VERSION 5.8 ;
BUSBITCHARS "[]" ;
DIVIDERCHAR "/" ;

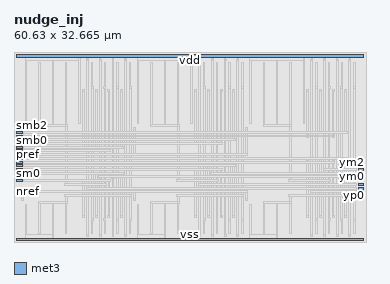
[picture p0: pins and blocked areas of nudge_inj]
MACRO nudge_inj
  CLASS BLOCK ;
  FOREIGN nudge_inj 0 0 ;
  ORIGIN 0 0 ;
  SIZE 60.630 BY 32.665 ;
  SYMMETRY X Y ;
  PIN nref
    DIRECTION INPUT ;
    USE SIGNAL ;
    PORT
      LAYER met3 ;
        RECT 0.460 8.455 1.400 8.795 ;
    END
  END nref
  PIN pref
    DIRECTION INPUT ;
    USE SIGNAL ;
    PORT
      LAYER met3 ;
        RECT 0.460 14.855 1.400 15.195 ;
    END
  END pref
  PIN sm0
    DIRECTION INPUT ;
    USE SIGNAL ;
    PORT
      LAYER met3 ;
        RECT 0.460 11.655 1.400 11.995 ;
    END
  END sm0
  PIN sm1
    DIRECTION INPUT ;
    USE SIGNAL ;
    PORT
      LAYER met3 ;
        RECT 0.460 12.935 1.400 13.275 ;
    END
  END sm1
  PIN sm2
    DIRECTION INPUT ;
    USE SIGNAL ;
    PORT
      LAYER met3 ;
        RECT 0.460 14.215 1.400 14.555 ;
    END
  END sm2
  PIN smb0
    DIRECTION INPUT ;
    USE SIGNAL ;
    PORT
      LAYER met3 ;
        RECT 0.460 16.135 1.400 16.475 ;
    END
  END smb0
  PIN smb1
    DIRECTION INPUT ;
    USE SIGNAL ;
    PORT
      LAYER met3 ;
        RECT 0.460 17.415 1.400 17.755 ;
    END
  END smb1
  PIN smb2
    DIRECTION INPUT ;
    USE SIGNAL ;
    PORT
      LAYER met3 ;
        RECT 0.460 18.695 1.400 19.035 ;
    END
  END smb2
  PIN sp0
    DIRECTION INPUT ;
    USE SIGNAL ;
    PORT
      LAYER met3 ;
        RECT 0.460 10.375 1.400 10.715 ;
    END
  END sp0
  PIN sp1
    DIRECTION INPUT ;
    USE SIGNAL ;
    PORT
      LAYER met3 ;
        RECT 0.460 12.295 1.400 12.635 ;
    END
  END sp1
  PIN sp2
    DIRECTION INPUT ;
    USE SIGNAL ;
    PORT
      LAYER met3 ;
        RECT 0.460 13.575 1.400 13.915 ;
    END
  END sp2
  PIN spb0
    DIRECTION INPUT ;
    USE SIGNAL ;
    PORT
      LAYER met3 ;
        RECT 0.460 15.495 1.400 15.835 ;
    END
  END spb0
  PIN spb1
    DIRECTION INPUT ;
    USE SIGNAL ;
    PORT
      LAYER met3 ;
        RECT 0.460 16.775 1.400 17.115 ;
    END
  END spb1
  PIN spb2
    DIRECTION INPUT ;
    USE SIGNAL ;
    PORT
      LAYER met3 ;
        RECT 0.460 18.055 1.400 18.395 ;
    END
  END spb2
  PIN vdd
    DIRECTION INOUT ;
    USE POWER ;
    PORT
      LAYER met3 ;
        RECT 0.460 31.705 60.170 32.205 ;
    END
  END vdd
  PIN vss
    DIRECTION INOUT ;
    USE GROUND ;
    PORT
      LAYER met3 ;
        RECT 0.460 0.185 60.170 0.685 ;
    END
  END vss
  PIN ym0
    DIRECTION OUTPUT ;
    USE SIGNAL ;
    PORT
      LAYER met3 ;
        RECT 59.230 11.015 60.170 11.355 ;
    END
  END ym0
  PIN ym1
    DIRECTION OUTPUT ;
    USE SIGNAL ;
    PORT
      LAYER met3 ;
        RECT 59.230 11.655 60.170 11.995 ;
    END
  END ym1
  PIN ym2
    DIRECTION OUTPUT ;
    USE SIGNAL ;
    PORT
      LAYER met3 ;
        RECT 59.230 12.295 60.170 12.635 ;
    END
  END ym2
  PIN yp0
    DIRECTION OUTPUT ;
    USE SIGNAL ;
    PORT
      LAYER met3 ;
        RECT 59.230 9.095 60.170 9.435 ;
    END
  END yp0
  PIN yp1
    DIRECTION OUTPUT ;
    USE SIGNAL ;
    PORT
      LAYER met3 ;
        RECT 59.230 9.735 60.170 10.075 ;
    END
  END yp1
  PIN yp2
    DIRECTION OUTPUT ;
    USE SIGNAL ;
    PORT
      LAYER met3 ;
        RECT 59.230 8.455 60.170 8.795 ;
    END
  END yp2
  OBS
    LAYER li1 ;
      RECT 0.000 0.000 60.630 32.665 ;
    LAYER met1 ;
      RECT 12.490 0.930 12.540 1.260 ;
      RECT 12.770 0.930 12.820 1.260 ;
      RECT 12.540 0.925 12.770 3.455 ;
      RECT 14.670 0.930 14.720 1.260 ;
      RECT 14.950 0.930 15.000 1.260 ;
      RECT 14.720 0.925 14.950 3.455 ;
      RECT 16.850 0.930 16.900 1.260 ;
      RECT 17.130 0.930 17.180 1.260 ;
      RECT 16.900 0.925 17.130 3.455 ;
      RECT 19.030 0.930 19.080 1.260 ;
      RECT 19.310 0.930 19.360 1.260 ;
      RECT 19.080 0.925 19.310 3.455 ;
      RECT 31.760 0.930 31.810 1.260 ;
      RECT 32.040 0.930 32.090 1.260 ;
      RECT 31.810 0.925 32.040 3.455 ;
      RECT 33.940 0.930 33.990 1.260 ;
      RECT 34.220 0.930 34.270 1.260 ;
      RECT 33.990 0.925 34.220 3.455 ;
      RECT 36.120 0.930 36.170 1.260 ;
      RECT 36.400 0.930 36.450 1.260 ;
      RECT 36.170 0.925 36.400 3.455 ;
      RECT 38.300 0.930 38.350 1.260 ;
      RECT 38.580 0.930 38.630 1.260 ;
      RECT 38.350 0.925 38.580 3.455 ;
      RECT 51.030 0.930 51.080 1.260 ;
      RECT 51.310 0.930 51.360 1.260 ;
      RECT 51.080 0.925 51.310 3.455 ;
      RECT 53.210 0.930 53.260 1.260 ;
      RECT 53.490 0.930 53.540 1.260 ;
      RECT 53.260 0.925 53.490 3.455 ;
      RECT 55.390 0.930 55.440 1.260 ;
      RECT 55.670 0.930 55.720 1.260 ;
      RECT 55.440 0.925 55.670 3.455 ;
      RECT 57.570 0.930 57.620 1.260 ;
      RECT 57.850 0.930 57.900 1.260 ;
      RECT 57.620 0.925 57.850 3.455 ;
      RECT 13.330 3.960 13.560 3.965 ;
      RECT 13.280 3.630 13.610 3.960 ;
      RECT 13.330 1.455 13.560 3.630 ;
      RECT 15.510 3.960 15.740 3.965 ;
      RECT 15.460 3.630 15.790 3.960 ;
      RECT 15.510 1.455 15.740 3.630 ;
      RECT 17.690 3.960 17.920 3.965 ;
      RECT 17.640 3.630 17.970 3.960 ;
      RECT 17.690 1.455 17.920 3.630 ;
      RECT 19.870 3.960 20.100 3.965 ;
      RECT 19.820 3.630 20.150 3.960 ;
      RECT 19.870 1.455 20.100 3.630 ;
      RECT 32.600 3.960 32.830 3.965 ;
      RECT 32.550 3.630 32.880 3.960 ;
      RECT 32.600 1.455 32.830 3.630 ;
      RECT 34.780 3.960 35.010 3.965 ;
      RECT 34.730 3.630 35.060 3.960 ;
      RECT 34.780 1.455 35.010 3.630 ;
      RECT 36.960 3.960 37.190 3.965 ;
      RECT 36.910 3.630 37.240 3.960 ;
      RECT 36.960 1.455 37.190 3.630 ;
      RECT 39.140 3.960 39.370 3.965 ;
      RECT 39.090 3.630 39.420 3.960 ;
      RECT 39.140 1.455 39.370 3.630 ;
      RECT 51.870 3.960 52.100 3.965 ;
      RECT 51.820 3.630 52.150 3.960 ;
      RECT 51.870 1.455 52.100 3.630 ;
      RECT 54.050 3.960 54.280 3.965 ;
      RECT 54.000 3.630 54.330 3.960 ;
      RECT 54.050 1.455 54.280 3.630 ;
      RECT 56.230 3.960 56.460 3.965 ;
      RECT 56.180 3.630 56.510 3.960 ;
      RECT 56.230 1.455 56.460 3.630 ;
      RECT 58.410 3.960 58.640 3.965 ;
      RECT 58.360 3.630 58.690 3.960 ;
      RECT 58.410 1.455 58.640 3.630 ;
      RECT 11.790 4.145 12.130 4.485 ;
      RECT 13.970 4.145 14.310 4.485 ;
      RECT 16.150 4.145 16.490 4.485 ;
      RECT 18.330 4.145 18.670 4.485 ;
      RECT 31.060 4.145 31.400 4.485 ;
      RECT 33.240 4.145 33.580 4.485 ;
      RECT 35.420 4.145 35.760 4.485 ;
      RECT 37.600 4.145 37.940 4.485 ;
      RECT 50.330 4.145 50.670 4.485 ;
      RECT 52.510 4.145 52.850 4.485 ;
      RECT 54.690 4.145 55.030 4.485 ;
      RECT 56.870 4.145 57.210 4.485 ;
      RECT 1.990 1.265 2.220 6.455 ;
      RECT 6.570 0.685 6.800 6.455 ;
      RECT 1.990 0.685 6.570 1.265 ;
      RECT 21.260 1.265 21.490 6.455 ;
      RECT 25.840 0.685 26.070 6.455 ;
      RECT 21.260 0.685 25.840 1.265 ;
      RECT 40.530 1.265 40.760 6.455 ;
      RECT 45.340 0.185 60.170 0.685 ;
      RECT 45.110 0.185 45.340 6.455 ;
      RECT 40.530 0.185 45.110 1.265 ;
      RECT 0.460 0.185 40.530 0.685 ;
      RECT 4.280 1.455 4.510 6.625 ;
      RECT 4.280 6.625 8.860 6.965 ;
      RECT 9.090 6.630 9.140 6.960 ;
      RECT 8.860 1.455 9.090 6.965 ;
      RECT 23.550 1.455 23.780 6.625 ;
      RECT 23.550 6.625 28.130 6.965 ;
      RECT 28.360 6.630 28.410 6.960 ;
      RECT 28.130 1.455 28.360 6.965 ;
      RECT 42.820 1.455 43.050 6.625 ;
      RECT 42.820 6.625 47.400 6.965 ;
      RECT 47.630 6.630 47.680 6.960 ;
      RECT 47.400 1.455 47.630 6.965 ;
      RECT 1.240 7.145 1.580 7.485 ;
      RECT 20.510 7.145 20.850 7.485 ;
      RECT 39.780 7.145 40.120 7.485 ;
      RECT 1.240 19.405 1.580 19.745 ;
      RECT 20.510 19.405 20.850 19.745 ;
      RECT 39.780 19.405 40.120 19.745 ;
      RECT 11.790 25.905 12.130 26.245 ;
      RECT 13.970 25.905 14.310 26.245 ;
      RECT 16.150 25.905 16.490 26.245 ;
      RECT 18.330 25.905 18.670 26.245 ;
      RECT 31.060 25.905 31.400 26.245 ;
      RECT 33.240 25.905 33.580 26.245 ;
      RECT 35.420 25.905 35.760 26.245 ;
      RECT 37.600 25.905 37.940 26.245 ;
      RECT 50.330 25.905 50.670 26.245 ;
      RECT 52.510 25.905 52.850 26.245 ;
      RECT 54.690 25.905 55.030 26.245 ;
      RECT 56.870 25.905 57.210 26.245 ;
      RECT 4.280 20.265 4.510 30.935 ;
      RECT 8.860 20.265 9.090 30.935 ;
      RECT 9.090 19.930 9.140 20.260 ;
      RECT 4.280 19.925 9.090 20.265 ;
      RECT 13.280 26.430 13.330 26.760 ;
      RECT 13.560 26.430 13.610 26.760 ;
      RECT 13.330 26.425 13.560 30.935 ;
      RECT 15.460 26.430 15.510 26.760 ;
      RECT 15.740 26.430 15.790 26.760 ;
      RECT 15.510 26.425 15.740 30.935 ;
      RECT 17.640 26.430 17.690 26.760 ;
      RECT 17.920 26.430 17.970 26.760 ;
      RECT 17.690 26.425 17.920 30.935 ;
      RECT 19.820 26.430 19.870 26.760 ;
      RECT 20.100 26.430 20.150 26.760 ;
      RECT 19.870 26.425 20.100 30.935 ;
      RECT 23.550 20.265 23.780 30.935 ;
      RECT 28.130 20.265 28.360 30.935 ;
      RECT 28.360 19.930 28.410 20.260 ;
      RECT 23.550 19.925 28.360 20.265 ;
      RECT 32.550 26.430 32.600 26.760 ;
      RECT 32.830 26.430 32.880 26.760 ;
      RECT 32.600 26.425 32.830 30.935 ;
      RECT 34.730 26.430 34.780 26.760 ;
      RECT 35.010 26.430 35.060 26.760 ;
      RECT 34.780 26.425 35.010 30.935 ;
      RECT 36.910 26.430 36.960 26.760 ;
      RECT 37.190 26.430 37.240 26.760 ;
      RECT 36.960 26.425 37.190 30.935 ;
      RECT 39.090 26.430 39.140 26.760 ;
      RECT 39.370 26.430 39.420 26.760 ;
      RECT 39.140 26.425 39.370 30.935 ;
      RECT 42.820 20.265 43.050 30.935 ;
      RECT 47.400 20.265 47.630 30.935 ;
      RECT 47.630 19.930 47.680 20.260 ;
      RECT 42.820 19.925 47.630 20.265 ;
      RECT 51.820 26.430 51.870 26.760 ;
      RECT 52.100 26.430 52.150 26.760 ;
      RECT 51.870 26.425 52.100 30.935 ;
      RECT 54.000 26.430 54.050 26.760 ;
      RECT 54.280 26.430 54.330 26.760 ;
      RECT 54.050 26.425 54.280 30.935 ;
      RECT 56.180 26.430 56.230 26.760 ;
      RECT 56.460 26.430 56.510 26.760 ;
      RECT 56.230 26.425 56.460 30.935 ;
      RECT 58.360 26.430 58.410 26.760 ;
      RECT 58.640 26.430 58.690 26.760 ;
      RECT 58.410 26.425 58.640 30.935 ;
      RECT 12.540 31.460 12.770 31.465 ;
      RECT 12.490 31.130 12.820 31.460 ;
      RECT 12.540 26.935 12.770 31.130 ;
      RECT 14.720 31.460 14.950 31.465 ;
      RECT 14.670 31.130 15.000 31.460 ;
      RECT 14.720 26.935 14.950 31.130 ;
      RECT 16.900 31.460 17.130 31.465 ;
      RECT 16.850 31.130 17.180 31.460 ;
      RECT 16.900 26.935 17.130 31.130 ;
      RECT 19.080 31.460 19.310 31.465 ;
      RECT 19.030 31.130 19.360 31.460 ;
      RECT 19.080 26.935 19.310 31.130 ;
      RECT 31.810 31.460 32.040 31.465 ;
      RECT 31.760 31.130 32.090 31.460 ;
      RECT 31.810 26.935 32.040 31.130 ;
      RECT 33.990 31.460 34.220 31.465 ;
      RECT 33.940 31.130 34.270 31.460 ;
      RECT 33.990 26.935 34.220 31.130 ;
      RECT 36.170 31.460 36.400 31.465 ;
      RECT 36.120 31.130 36.450 31.460 ;
      RECT 36.170 26.935 36.400 31.130 ;
      RECT 38.350 31.460 38.580 31.465 ;
      RECT 38.300 31.130 38.630 31.460 ;
      RECT 38.350 26.935 38.580 31.130 ;
      RECT 51.080 31.460 51.310 31.465 ;
      RECT 51.030 31.130 51.360 31.460 ;
      RECT 51.080 26.935 51.310 31.130 ;
      RECT 53.260 31.460 53.490 31.465 ;
      RECT 53.210 31.130 53.540 31.460 ;
      RECT 53.260 26.935 53.490 31.130 ;
      RECT 55.440 31.460 55.670 31.465 ;
      RECT 55.390 31.130 55.720 31.460 ;
      RECT 55.440 26.935 55.670 31.130 ;
      RECT 57.620 31.460 57.850 31.465 ;
      RECT 57.570 31.130 57.900 31.460 ;
      RECT 57.620 26.935 57.850 31.130 ;
      RECT 1.990 20.435 2.220 31.125 ;
      RECT 6.570 20.435 6.800 31.125 ;
      RECT 21.260 20.435 21.490 31.125 ;
      RECT 25.840 20.435 26.070 31.125 ;
      RECT 40.530 20.435 40.760 31.125 ;
      RECT 45.110 20.435 45.340 31.125 ;
      RECT 1.990 31.125 11.150 31.705 ;
      RECT 11.150 20.435 11.380 31.705 ;
      RECT 21.260 31.125 30.420 31.705 ;
      RECT 30.420 20.435 30.650 31.705 ;
      RECT 0.460 31.705 40.530 32.205 ;
      RECT 40.530 31.125 49.690 32.205 ;
      RECT 49.690 20.435 49.920 32.205 ;
      RECT 49.920 31.705 60.170 32.205 ;
    LAYER met2 ;
      RECT 0.460 0.185 60.170 0.685 ;
      RECT 8.790 7.800 9.160 8.170 ;
      RECT 8.825 6.960 9.125 7.800 ;
      RECT 8.810 6.630 9.140 6.960 ;
      RECT 28.060 7.800 28.430 8.170 ;
      RECT 28.095 6.960 28.395 7.800 ;
      RECT 28.080 6.630 28.410 6.960 ;
      RECT 47.330 7.800 47.700 8.170 ;
      RECT 47.365 6.960 47.665 7.800 ;
      RECT 47.350 6.630 47.680 6.960 ;
      RECT 1.225 8.440 1.595 8.810 ;
      RECT 1.260 7.480 1.560 8.440 ;
      RECT 1.245 7.150 1.575 7.480 ;
      RECT 20.495 8.440 20.865 8.810 ;
      RECT 20.530 7.480 20.830 8.440 ;
      RECT 20.515 7.150 20.845 7.480 ;
      RECT 39.765 8.440 40.135 8.810 ;
      RECT 39.800 7.480 40.100 8.440 ;
      RECT 39.785 7.150 40.115 7.480 ;
      RECT 11.775 10.360 12.145 10.730 ;
      RECT 11.810 4.480 12.110 10.360 ;
      RECT 11.795 4.150 12.125 4.480 ;
      RECT 16.135 10.360 16.505 10.730 ;
      RECT 16.170 4.480 16.470 10.360 ;
      RECT 16.155 4.150 16.485 4.480 ;
      RECT 13.955 11.640 14.325 12.010 ;
      RECT 13.990 4.480 14.290 11.640 ;
      RECT 13.975 4.150 14.305 4.480 ;
      RECT 18.315 11.640 18.685 12.010 ;
      RECT 18.350 4.480 18.650 11.640 ;
      RECT 18.335 4.150 18.665 4.480 ;
      RECT 31.045 12.280 31.415 12.650 ;
      RECT 31.080 4.480 31.380 12.280 ;
      RECT 31.065 4.150 31.395 4.480 ;
      RECT 35.405 12.280 35.775 12.650 ;
      RECT 35.440 4.480 35.740 12.280 ;
      RECT 35.425 4.150 35.755 4.480 ;
      RECT 33.225 12.920 33.595 13.290 ;
      RECT 33.260 4.480 33.560 12.920 ;
      RECT 33.245 4.150 33.575 4.480 ;
      RECT 37.585 12.920 37.955 13.290 ;
      RECT 37.620 4.480 37.920 12.920 ;
      RECT 37.605 4.150 37.935 4.480 ;
      RECT 50.315 13.560 50.685 13.930 ;
      RECT 50.350 4.480 50.650 13.560 ;
      RECT 50.335 4.150 50.665 4.480 ;
      RECT 54.675 13.560 55.045 13.930 ;
      RECT 54.710 4.480 55.010 13.560 ;
      RECT 54.695 4.150 55.025 4.480 ;
      RECT 52.495 14.200 52.865 14.570 ;
      RECT 52.530 4.480 52.830 14.200 ;
      RECT 52.515 4.150 52.845 4.480 ;
      RECT 56.855 14.200 57.225 14.570 ;
      RECT 56.890 4.480 57.190 14.200 ;
      RECT 56.875 4.150 57.205 4.480 ;
      RECT 1.245 19.410 1.575 19.740 ;
      RECT 1.260 15.210 1.560 19.410 ;
      RECT 1.225 14.840 1.595 15.210 ;
      RECT 20.515 19.410 20.845 19.740 ;
      RECT 20.530 15.210 20.830 19.410 ;
      RECT 20.495 14.840 20.865 15.210 ;
      RECT 39.785 19.410 40.115 19.740 ;
      RECT 39.800 15.210 40.100 19.410 ;
      RECT 39.765 14.840 40.135 15.210 ;
      RECT 8.810 19.930 9.140 20.260 ;
      RECT 8.825 10.090 9.125 19.930 ;
      RECT 8.790 9.720 9.160 10.090 ;
      RECT 28.080 19.930 28.410 20.260 ;
      RECT 28.095 10.730 28.395 19.930 ;
      RECT 28.060 10.360 28.430 10.730 ;
      RECT 47.350 19.930 47.680 20.260 ;
      RECT 47.365 10.730 47.665 19.930 ;
      RECT 47.330 10.360 47.700 10.730 ;
      RECT 11.795 25.910 12.125 26.240 ;
      RECT 11.810 15.850 12.110 25.910 ;
      RECT 11.775 15.480 12.145 15.850 ;
      RECT 13.975 25.910 14.305 26.240 ;
      RECT 13.990 16.490 14.290 25.910 ;
      RECT 13.955 16.120 14.325 16.490 ;
      RECT 16.155 25.910 16.485 26.240 ;
      RECT 16.170 15.850 16.470 25.910 ;
      RECT 16.135 15.480 16.505 15.850 ;
      RECT 18.335 25.910 18.665 26.240 ;
      RECT 18.350 16.490 18.650 25.910 ;
      RECT 18.315 16.120 18.685 16.490 ;
      RECT 31.065 25.910 31.395 26.240 ;
      RECT 31.080 17.130 31.380 25.910 ;
      RECT 31.045 16.760 31.415 17.130 ;
      RECT 33.245 25.910 33.575 26.240 ;
      RECT 33.260 17.770 33.560 25.910 ;
      RECT 33.225 17.400 33.595 17.770 ;
      RECT 35.425 25.910 35.755 26.240 ;
      RECT 35.440 17.130 35.740 25.910 ;
      RECT 35.405 16.760 35.775 17.130 ;
      RECT 37.605 25.910 37.935 26.240 ;
      RECT 37.620 17.770 37.920 25.910 ;
      RECT 37.585 17.400 37.955 17.770 ;
      RECT 50.335 25.910 50.665 26.240 ;
      RECT 50.350 18.410 50.650 25.910 ;
      RECT 50.315 18.040 50.685 18.410 ;
      RECT 52.515 25.910 52.845 26.240 ;
      RECT 52.530 19.050 52.830 25.910 ;
      RECT 52.495 18.680 52.865 19.050 ;
      RECT 54.695 25.910 55.025 26.240 ;
      RECT 54.710 18.410 55.010 25.910 ;
      RECT 54.675 18.040 55.045 18.410 ;
      RECT 56.875 25.910 57.205 26.240 ;
      RECT 56.890 19.050 57.190 25.910 ;
      RECT 56.855 18.680 57.225 19.050 ;
      RECT 13.280 26.430 13.610 26.760 ;
      RECT 13.295 10.090 13.595 26.430 ;
      RECT 13.260 9.720 13.630 10.090 ;
      RECT 13.295 3.960 13.595 9.720 ;
      RECT 13.280 3.630 13.610 3.960 ;
      RECT 15.460 26.430 15.790 26.760 ;
      RECT 15.475 10.090 15.775 26.430 ;
      RECT 15.440 9.720 15.810 10.090 ;
      RECT 15.475 3.960 15.775 9.720 ;
      RECT 15.460 3.630 15.790 3.960 ;
      RECT 17.640 26.430 17.970 26.760 ;
      RECT 17.655 8.170 17.955 26.430 ;
      RECT 17.620 7.800 17.990 8.170 ;
      RECT 17.655 3.960 17.955 7.800 ;
      RECT 17.640 3.630 17.970 3.960 ;
      RECT 19.820 26.430 20.150 26.760 ;
      RECT 19.835 8.170 20.135 26.430 ;
      RECT 19.800 7.800 20.170 8.170 ;
      RECT 19.835 3.960 20.135 7.800 ;
      RECT 19.820 3.630 20.150 3.960 ;
      RECT 32.550 26.430 32.880 26.760 ;
      RECT 32.565 10.730 32.865 26.430 ;
      RECT 32.530 10.360 32.900 10.730 ;
      RECT 32.565 3.960 32.865 10.360 ;
      RECT 32.550 3.630 32.880 3.960 ;
      RECT 34.730 26.430 35.060 26.760 ;
      RECT 34.745 10.730 35.045 26.430 ;
      RECT 34.710 10.360 35.080 10.730 ;
      RECT 34.745 3.960 35.045 10.360 ;
      RECT 34.730 3.630 35.060 3.960 ;
      RECT 36.910 26.430 37.240 26.760 ;
      RECT 36.925 8.170 37.225 26.430 ;
      RECT 36.890 7.800 37.260 8.170 ;
      RECT 36.925 3.960 37.225 7.800 ;
      RECT 36.910 3.630 37.240 3.960 ;
      RECT 39.090 26.430 39.420 26.760 ;
      RECT 39.105 8.170 39.405 26.430 ;
      RECT 39.070 7.800 39.440 8.170 ;
      RECT 39.105 3.960 39.405 7.800 ;
      RECT 39.090 3.630 39.420 3.960 ;
      RECT 51.820 26.430 52.150 26.760 ;
      RECT 51.835 10.730 52.135 26.430 ;
      RECT 51.800 10.360 52.170 10.730 ;
      RECT 51.835 3.960 52.135 10.360 ;
      RECT 51.820 3.630 52.150 3.960 ;
      RECT 54.000 26.430 54.330 26.760 ;
      RECT 54.015 10.730 54.315 26.430 ;
      RECT 53.980 10.360 54.350 10.730 ;
      RECT 54.015 3.960 54.315 10.360 ;
      RECT 54.000 3.630 54.330 3.960 ;
      RECT 56.180 26.430 56.510 26.760 ;
      RECT 56.195 8.170 56.495 26.430 ;
      RECT 56.160 7.800 56.530 8.170 ;
      RECT 56.195 3.960 56.495 7.800 ;
      RECT 56.180 3.630 56.510 3.960 ;
      RECT 58.360 26.430 58.690 26.760 ;
      RECT 58.375 8.170 58.675 26.430 ;
      RECT 58.340 7.800 58.710 8.170 ;
      RECT 58.375 3.960 58.675 7.800 ;
      RECT 58.360 3.630 58.690 3.960 ;
      RECT 12.490 31.130 12.820 31.460 ;
      RECT 12.505 9.450 12.805 31.130 ;
      RECT 12.470 9.080 12.840 9.450 ;
      RECT 12.505 1.260 12.805 9.080 ;
      RECT 12.490 0.930 12.820 1.260 ;
      RECT 14.670 31.130 15.000 31.460 ;
      RECT 14.685 11.370 14.985 31.130 ;
      RECT 14.650 11.000 15.020 11.370 ;
      RECT 14.685 1.260 14.985 11.000 ;
      RECT 14.670 0.930 15.000 1.260 ;
      RECT 16.850 31.130 17.180 31.460 ;
      RECT 16.865 11.370 17.165 31.130 ;
      RECT 16.830 11.000 17.200 11.370 ;
      RECT 16.865 1.260 17.165 11.000 ;
      RECT 16.850 0.930 17.180 1.260 ;
      RECT 19.030 31.130 19.360 31.460 ;
      RECT 19.045 9.450 19.345 31.130 ;
      RECT 19.010 9.080 19.380 9.450 ;
      RECT 19.045 1.260 19.345 9.080 ;
      RECT 19.030 0.930 19.360 1.260 ;
      RECT 31.760 31.130 32.090 31.460 ;
      RECT 31.775 10.090 32.075 31.130 ;
      RECT 31.740 9.720 32.110 10.090 ;
      RECT 31.775 1.260 32.075 9.720 ;
      RECT 31.760 0.930 32.090 1.260 ;
      RECT 33.940 31.130 34.270 31.460 ;
      RECT 33.955 12.010 34.255 31.130 ;
      RECT 33.920 11.640 34.290 12.010 ;
      RECT 33.955 1.260 34.255 11.640 ;
      RECT 33.940 0.930 34.270 1.260 ;
      RECT 36.120 31.130 36.450 31.460 ;
      RECT 36.135 12.010 36.435 31.130 ;
      RECT 36.100 11.640 36.470 12.010 ;
      RECT 36.135 1.260 36.435 11.640 ;
      RECT 36.120 0.930 36.450 1.260 ;
      RECT 38.300 31.130 38.630 31.460 ;
      RECT 38.315 10.090 38.615 31.130 ;
      RECT 38.280 9.720 38.650 10.090 ;
      RECT 38.315 1.260 38.615 9.720 ;
      RECT 38.300 0.930 38.630 1.260 ;
      RECT 51.030 31.130 51.360 31.460 ;
      RECT 51.045 8.810 51.345 31.130 ;
      RECT 51.010 8.440 51.380 8.810 ;
      RECT 51.045 1.260 51.345 8.440 ;
      RECT 51.030 0.930 51.360 1.260 ;
      RECT 53.210 31.130 53.540 31.460 ;
      RECT 53.225 12.650 53.525 31.130 ;
      RECT 53.190 12.280 53.560 12.650 ;
      RECT 53.225 1.260 53.525 12.280 ;
      RECT 53.210 0.930 53.540 1.260 ;
      RECT 55.390 31.130 55.720 31.460 ;
      RECT 55.405 12.650 55.705 31.130 ;
      RECT 55.370 12.280 55.740 12.650 ;
      RECT 55.405 1.260 55.705 12.280 ;
      RECT 55.390 0.930 55.720 1.260 ;
      RECT 57.570 31.130 57.900 31.460 ;
      RECT 57.585 8.810 57.885 31.130 ;
      RECT 57.550 8.440 57.920 8.810 ;
      RECT 57.585 1.260 57.885 8.440 ;
      RECT 57.570 0.930 57.900 1.260 ;
      RECT 0.460 31.705 60.170 32.205 ;
    LAYER met3 ;
      RECT 8.725 7.815 20.235 8.155 ;
      RECT 27.995 7.815 39.505 8.155 ;
      RECT 47.265 7.815 58.775 8.155 ;
      RECT 1.700 8.455 40.200 8.795 ;
      RECT 50.945 8.455 58.930 8.795 ;
      RECT 12.405 9.095 58.930 9.435 ;
      RECT 8.725 9.735 15.875 10.075 ;
      RECT 31.675 9.735 58.930 10.075 ;
      RECT 1.700 10.375 16.570 10.715 ;
      RECT 27.995 10.375 35.145 10.715 ;
      RECT 47.265 10.375 54.415 10.715 ;
      RECT 14.585 11.015 58.930 11.355 ;
      RECT 1.700 11.655 18.750 11.995 ;
      RECT 33.855 11.655 58.930 11.995 ;
      RECT 1.700 12.295 35.840 12.635 ;
      RECT 53.125 12.295 58.930 12.635 ;
      RECT 1.700 12.935 38.020 13.275 ;
      RECT 1.700 13.575 55.110 13.915 ;
      RECT 1.700 14.215 57.290 14.555 ;
      RECT 1.700 14.855 40.200 15.195 ;
      RECT 1.700 15.495 16.570 15.835 ;
      RECT 1.700 16.135 18.750 16.475 ;
      RECT 1.700 16.775 35.840 17.115 ;
      RECT 1.700 17.415 38.020 17.755 ;
      RECT 1.700 18.055 55.110 18.395 ;
      RECT 1.700 18.695 57.290 19.035 ;
  END
END nudge_inj

END LIBRARY
